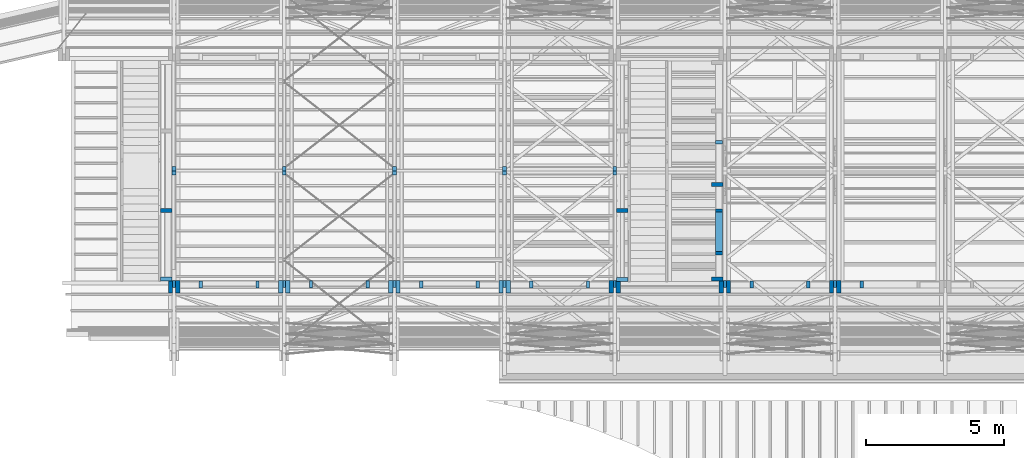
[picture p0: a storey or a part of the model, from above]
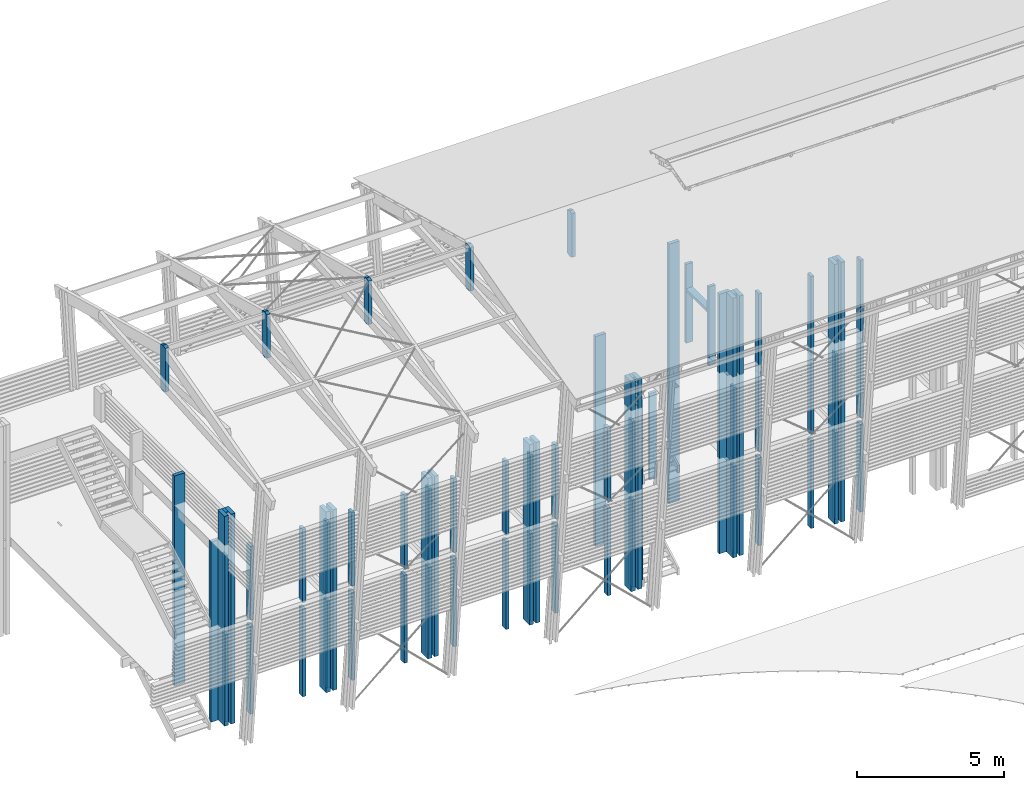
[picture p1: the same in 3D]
Properties of the parts of a building model (IFC2X3)

# File
Description: ViewDefinition [CoordinationView_V2.0]
File name: Export_V2
Time: 2021-08-31T17:11:27
Made in: cadwork

# IfcSite
RefElevation: 0 m

# IfcBuildingStorey, Storey 1
In: Building 1
Elevation: 0 m

# IfcBeam (1829)
In: Storey 1
Name | Material | Width (m) | Height (m) | Length (m) | CrossSectionArea (m2) | OuterfaceArea (m2) | TotalSurfaceArea (m2) | GrossVolume (m3) | NetVolume (m3) | GrossWeight | NetWeight | Group | SubGroup | Utilisateur 1
187 x garde corp | Moabi | 0.04 | 0.2 | 3.8048 | 1.6 | 1.8263 | 1.8423 | 0.0304 | 0.0304 | 19.785 | 19.785 | garde corp | Garde-corps | S-BEAM-____-OTLN
369 x garde corp | Moabi | 0.04 | 0.2 | 3.806 | 1.6 | 1.8269 | 1.8429 | 0.0304 | 0.0304 | 19.7912 | 19.7912 | garde corp | Garde-corps | S-BEAM-____-OTLN
25 x Sommier Coursive | GL28h | 0.14 | 0.32 | 2.6285 | 14.336 | 2.3831 | 2.4727 | 0.1178 | 0.1121 | 0.5312 | 0.5058 | structure poteau / poutre | Structure secondaire
19 x Sous-glace | GL28h | 0.12 | 0.12 | 4.0038 | 1.728 | 1.921 | 1.9498 | 0.0577 | 0.0576 | 0.2601 | 0.26 | structure poteau / poutre | Façade OB
66 x garde corp | Moabi | 0.04 | 0.2 | 2 | 1.6 | 0.96 | 0.976 | 0.016 | 0.016 | 10.4 | 10.4 | garde corp | Garde-corps | S-BEAM-____-OTLN
74 x Solive | GL28h | 0.07 | 0.22 | 3.86 | 3.388 | 2.2388 | 2.2696 | 0.0594 | 0.0594 | 0.2682 | 0.2682 | plancher R+2 | Plancher Exterieur | S-BEAM-____-OTLN
14 x Solive | GL28h | 0.07 | 0.22 | 1.53 | 3.388 | 0.8874 | 0.9182 | 0.0236 | 0.0236 | 0.1063 | 0.1063 | plancher R+1 | Plancher Exterieur | S-BEAM-____-OTLN
13 x Solive | GL28h | 0.07 | 0.22 | 1.58 | 3.388 | 0.9164 | 0.9472 | 0.0243 | 0.0243 | 0.1098 | 0.1098 | plancher R+2 | Plancher Exterieur | S-BEAM-____-OTLN
69 x Solive | GL28h | 0.07 | 0.22 | 3.86 | 3.388 | 2.2388 | 2.2696 | 0.0594 | 0.0594 | 0.2682 | 0.2682 | plancher R+1 | Plancher Exterieur | S-BEAM-____-OTLN
4 x Sommier | GL28h | 0.1 | 0.3 | 9.1632 | 9 | 7.3305 | 7.3905 | 0.2749 | 0.2749 | 1.2401 | 1.2401 | structure poteau / poutre | Structure primaire | S-BEAM-____-OTLN
188 x garde corp | Moabi | 0.04 | 0.2 | 3.8047 | 1.6 | 1.8263 | 1.8423 | 0.0304 | 0.0304 | 19.7845 | 19.7845 | garde corp | Garde-corps | S-BEAM-____-OTLN
28 x Sous-glace | GL28h | 0.12 | 0.12 | 8.0032 | 1.728 | 3.8415 | 3.8703 | 0.1152 | 0.1152 | 0.5199 | 0.5199 | structure poteau / poutre | Plancher intérieur
garde corp | Moabi | 0.04 | 0.2 | 2.8818 | 1.6 | 1.3384 | 1.3544 | 0.0231 | 0.0223 | 14.9852 | 14.4634 | garde corp | Garde-corps | S-BEAM-____-OTLN
24 x Arbalétrier | GL28h | 0.14 | 0.46 | 7.5286 | 29.624 | 8.9626 | 9.0914 | 0.4848 | 0.4809 | 2.1871 | 2.1692 | charpente | Surtoiture | S-BEAM-____-OTLN
6 x Arbalétrier | GL28h | 0.07 | 0.22 | 1.2244 | 3.388 | 0.6936 | 0.7244 | 0.0189 | 0.0184 | 0.0851 | 0.083 | charpente | Surtoiture | S-BEAM-____-OTLN
36 x garde corp | Moabi | 0.04 | 0.2 | 0.9516 | 1.6 | 0.4568 | 0.4728 | 0.0076 | 0.0076 | 4.9482 | 4.9482 | garde corp | Garde-corps | S-BEAM-____-OTLN
2 x Solive | GL28h | 0.07 | 0.22 | 0.8113 | 3.388 | 0.4705 | 0.5013 | 0.0125 | 0.0125 | 0.0564 | 0.0564 | plancher R+1 | Plancher Exterieur | S-BEAM-____-OTLN
2 x pannes | GL28h | 0.07 | 0.22 | 34.1022 | 3.388 | 19.7782 | 19.809 | 0.5252 | 0.5251 | 2.3691 | 2.369 | charpente | Empannage | S-BEAM-____-OTLN
Buton | GL28h | 0.26 | 0.32 | 7.7232 | 26.624 | 8.9589 | 9.1253 | 0.6426 | 0.6426 | 2.8987 | 2.8987 | structure poteau / poutre | Structure primaire | S-BEAM-____-OTLN
40 x Sommier | GL28h | 0.16 | 0.46 | 7.9632 | 33.856 | 9.8743 | 10.0215 | 0.5861 | 0.5861 | 2.6439 | 2.6439 | structure poteau / poutre | Structure primaire | S-BEAM-____-OTLN
8 x carrelet | GL28h | 0.07 | 0.07 | 3.5 | 0.343 | 0.98 | 0.9898 | 0.0172 | 0.0172 | 0.0774 | 0.0774 | plancher extérieur | Platelage
14 x Solive | GL28h | 0.07 | 0.22 | 1.58 | 3.388 | 0.9164 | 0.9472 | 0.0243 | 0.0243 | 0.1098 | 0.1098 | plancher R+1 | Plancher Exterieur | S-BEAM-____-OTLN
16 x garde corp | Moabi | 0.04 | 0.2 | 4.2356 | 1.6 | 2.0331 | 2.0491 | 0.0339 | 0.0339 | 22.0249 | 22.0249 | garde corp | Garde-corps | S-BEAM-____-OTLN
2 x garde corp | Moabi | 0.04 | 0.2 | 1.3533 | 1.6 | 0.6042 | 0.6202 | 0.0108 | 0.01 | 7.0372 | 6.5092 | garde corp | Garde-corps | S-BEAM-____-OTLN
15 x Solive | GL28h | 0.07 | 0.22 | 0.4614 | 3.388 | 0.2676 | 0.2984 | 0.0071 | 0.0071 | 0.0321 | 0.0321 | plancher R+1 | Plancher Exterieur | S-BEAM-____-OTLN
garde corp | Moabi | 0.04 | 0.2 | 2.6655 | 1.6 | 1.234 | 1.25 | 0.0213 | 0.0205 | 13.8608 | 13.3328 | garde corp | Garde-corps | S-BEAM-____-OTLN
2 x Sous-glace | GL28h | 0.12 | 0.12 | 3.5091 | 1.728 | 1.6844 | 1.7132 | 0.0505 | 0.0505 | 0.2279 | 0.2279 | structure poteau / poutre | Plancher intérieur
4 x Buton | GL28h | 0.26 | 0.52 | 2.3516 | 70.304 | 3.6685 | 3.9389 | 0.3179 | 0.3179 | 1.4342 | 1.4342 | structure poteau / poutre | Structure primaire | S-BEAM-____-OTLN
41 x Buton | GL28h | 0.26 | 0.26 | 3.58 | 17.576 | 3.7232 | 3.8584 | 0.242 | 0.242 | 1.0917 | 1.0917 | structure poteau / poutre | Structure primaire | S-BEAM-____-OTLN
14 x garde corp | Moabi | 0.04 | 0.2 | 3.819 | 1.6 | 1.8331 | 1.8491 | 0.0306 | 0.0306 | 19.8588 | 19.8588 | garde corp | Garde-corps | S-BEAM-____-OTLN
30 x Sommier | GL28h | 0.1 | 0.1 | 7.9632 | 1 | 3.1853 | 3.2053 | 0.0796 | 0.0796 | 0.3592 | 0.3592 | structure poteau / poutre | Structure primaire | S-BEAM-____-OTLN
15 x Buton | GL28h | 0.09 | 0.22 | 3.86 | 4.356 | 2.3932 | 2.4328 | 0.0764 | 0.0764 | 0.3448 | 0.3448 | charpente | Surtoiture
15 x Poutre - Bois de construction | GL28h | 0.07 | 0.07 | 16.14 | 0.343 | 4.5192 | 4.529 | 0.0791 | 0.0791 | 0.3568 | 0.3568 | plancher R+2
2 x pannes | GL28h | 0.07 | 0.22 | 34.056 | 3.388 | 19.7515 | 19.7823 | 0.5245 | 0.5244 | 2.3659 | 2.3658 | charpente | Empannage | S-BEAM-____-OTLN
2 x pannes | GL28h | 0.07 | 0.22 | 34.1252 | 3.388 | 19.7916 | 19.8224 | 0.5255 | 0.5255 | 2.3707 | 2.3706 | charpente | Empannage | S-BEAM-____-OTLN
2 x garde corp | Moabi | 0.04 | 0.2 | 1.4537 | 1.6 | 0.6523 | 0.6683 | 0.0116 | 0.0108 | 7.559 | 7.031 | garde corp | Garde-corps | S-BEAM-____-OTLN
2 x pannes | GL28h | 0.07 | 0.22 | 34.0791 | 3.388 | 19.7648 | 19.7956 | 0.5248 | 0.5248 | 2.3675 | 2.3674 | charpente | Empannage | S-BEAM-____-OTLN
2 x pannes | GL28h | 0.07 | 0.22 | 34.1483 | 3.388 | 19.805 | 19.8358 | 0.5259 | 0.5259 | 2.3723 | 2.3722 | charpente | Empannage | S-BEAM-____-OTLN
32 x garde corp | Moabi | 0.04 | 0.2 | 6.9116 | 1.6 | 3.3176 | 3.3336 | 0.0553 | 0.0553 | 35.9402 | 35.9402 | garde corp | Garde-corps | S-BEAM-____-OTLN
garde corp | Moabi | 0.04 | 0.2 | 2.5473 | 1.6 | 1.1778 | 1.1938 | 0.0204 | 0.0196 | 13.246 | 12.7241 | garde corp | Garde-corps | S-BEAM-____-OTLN
6 x carrelet | GL28h | 0.05 | 0.08 | 20.42 | 0.32 | 5.3092 | 5.3172 | 0.0817 | 0.0817 | 0.3685 | 0.3685 | charpente | Empannage | S-BEAM-____-OTLN
2 x garde corp | Moabi | 0.04 | 0.2 | 3.0669 | 1.6 | 1.4267 | 1.4427 | 0.0245 | 0.0237 | 15.9481 | 15.4201 | garde corp | Garde-corps | S-BEAM-____-OTLN
pannes | GL28h | 0.09 | 0.22 | 34.1813 | 4.356 | 21.1911 | 21.2307 | 0.6768 | 0.6767 | 3.053 | 3.0529 | charpente | Empannage
2 x pannes | GL28h | 0.07 | 0.22 | 34.0329 | 3.388 | 19.7381 | 19.7689 | 0.5241 | 0.5241 | 2.3643 | 2.3642 | charpente | Empannage | S-BEAM-____-OTLN
14 x Poutre - Bois de construction | GL28h | 0.07 | 0.07 | 4.02 | 0.343 | 1.1256 | 1.1354 | 0.0197 | 0.0197 | 0.0889 | 0.0889 | plancher R+2
2 x pannes | GL28h | 0.07 | 0.22 | 33.9637 | 3.388 | 19.6979 | 19.7287 | 0.523 | 0.523 | 2.3595 | 2.3593 | charpente | Empannage | S-BEAM-____-OTLN
pannes | GL28h | 0.09 | 0.22 | 34.1717 | 4.356 | 21.1852 | 21.2248 | 0.6766 | 0.6766 | 3.0522 | 3.052 | charpente | Empannage
2 x garde corp | Moabi | 0.04 | 0.2 | 1.1693 | 1.6 | 0.5159 | 0.5319 | 0.0094 | 0.0085 | 6.0806 | 5.5526 | garde corp | Garde-corps | S-BEAM-____-OTLN
2 x pannes | GL28h | 0.09 | 0.22 | 33.9871 | 4.356 | 21.0707 | 21.1103 | 0.6729 | 0.6729 | 3.0357 | 3.0355 | charpente | Empannage
2 x garde corp | Moabi | 0.04 | 0.2 | 1.0188 | 1.6 | 0.4436 | 0.4596 | 0.0082 | 0.0073 | 5.2979 | 4.7699 | garde corp | Garde-corps | S-BEAM-____-OTLN
2 x pannes | GL28h | 0.07 | 0.22 | 34.0099 | 3.388 | 19.7247 | 19.7555 | 0.5238 | 0.5237 | 2.3627 | 2.3626 | charpente | Empannage | S-BEAM-____-OTLN
12 x potelet | GL28h | 0.07 | 0.168 | 0.38 | 1.9757 | 0.1809 | 0.2044 | 0.0045 | 0.0045 | 0.0202 | 0.0202 | charpente | Surtoiture
2 x garde corp | Moabi | 0.04 | 0.2 | 2.9833 | 1.6 | 1.3866 | 1.4026 | 0.0239 | 0.0231 | 15.5132 | 14.9852 | garde corp | Garde-corps | S-BEAM-____-OTLN
6 x Rive | GL28h | 0.07 | 0.22 | 3.58 | 3.388 | 2.0764 | 2.1072 | 0.0551 | 0.0551 | 0.2487 | 0.2487 | façade | Structure primaire | S-BEAM-____-OTLN
14 x Sous-glace | GL28h | 0.1 | 0.1 | 4.0064 | 1 | 1.6014 | 1.6214 | 0.0401 | 0.04 | 0.1807 | 0.1806 | structure poteau / poutre | Plancher intérieur
2 x Buton | GL28h | 0.26 | 0.52 | 2.74 | 70.304 | 4.2744 | 4.5448 | 0.3704 | 0.3704 | 1.6711 | 1.6711 | structure poteau / poutre | Structure primaire | S-BEAM-____-OTLN
garde corp | Moabi | 0.04 | 0.2 | 2.5986 | 1.6 | 1.2019 | 1.2179 | 0.0208 | 0.02 | 13.513 | 12.985 | garde corp | Garde-corps | S-BEAM-____-OTLN
2 x garde corp | Moabi | 0.04 | 0.2 | 1.069 | 1.6 | 0.4677 | 0.4837 | 0.0086 | 0.0077 | 5.5588 | 5.0308 | garde corp | Garde-corps | S-BEAM-____-OTLN
2 x garde corp | Moabi | 0.04 | 0.2 | 2.9164 | 1.6 | 1.3545 | 1.3705 | 0.0233 | 0.0225 | 15.1654 | 14.6373 | garde corp | Garde-corps | S-BEAM-____-OTLN
Sous-glace | GL28h | 0.12 | 0.12 | 4.0038 | 1.728 | 1.921 | 1.9498 | 0.0577 | 0.0576 | 0.2601 | 0.26 | structure poteau / poutre | Plancher intérieur
24 x Entrait | GL28h | 0.14 | 0.32 | 10.6244 | 14.336 | 9.7694 | 9.859 | 0.476 | 0.4757 | 2.1471 | 2.146 | charpente | Surtoiture | S-BEAM-____-OTLN
4 x Buton | GL28h | 0.26 | 0.26 | 2.3516 | 17.576 | 2.4456 | 2.5808 | 0.159 | 0.159 | 0.7171 | 0.7171 | structure poteau / poutre | Structure primaire | S-BEAM-____-OTLN
garde corp | Moabi | 0.04 | 0.2 | 1.4871 | 1.6 | 0.6684 | 0.6844 | 0.0119 | 0.0111 | 7.7329 | 7.205 | garde corp | Garde-corps | S-BEAM-____-OTLN
garde corp | Moabi | 0.04 | 0.14 | 10.7403 | 0.784 | 3.8665 | 3.8777 | 0.0601 | 0.0601 | 39.0948 | 39.0948 | garde corp | Garde-corps | S-BEAM-____-OTLN
2 x garde corp | Moabi | 0.04 | 0.2 | 1.4035 | 1.6 | 0.6282 | 0.6442 | 0.0112 | 0.0104 | 7.2981 | 6.7701 | garde corp | Garde-corps | S-BEAM-____-OTLN
2 x garde corp | Moabi | 0.04 | 0.2 | 1.5038 | 1.6 | 0.6764 | 0.6924 | 0.012 | 0.0112 | 7.8199 | 7.2919 | garde corp | Garde-corps | S-BEAM-____-OTLN
2 x garde corp | Moabi | 0.04 | 0.2 | 1.3868 | 1.6 | 0.6202 | 0.6362 | 0.0111 | 0.0103 | 7.2112 | 6.6831 | garde corp | Garde-corps | S-BEAM-____-OTLN
2 x Buton | GL28h | 0.26 | 0.26 | 2.74 | 17.576 | 2.8496 | 2.9848 | 0.1852 | 0.1852 | 0.8356 | 0.8356 | structure poteau / poutre | Structure primaire | S-BEAM-____-OTLN
Solive | GL28h | 0.07 | 0.22 | 3.413 | 3.388 | 1.9717 | 2.0025 | 0.0526 | 0.0523 | 0.2371 | 0.236 | plancher R+1 | Plancher Exterieur | S-BEAM-____-OTLN
2 x garde corp | Moabi | 0.04 | 0.2 | 1.3366 | 1.6 | 0.5961 | 0.6121 | 0.0107 | 0.0099 | 6.9503 | 6.4222 | garde corp | Garde-corps | S-BEAM-____-OTLN
25 x Sommier Coursive | GL28h | 0.14 | 0.32 | 2.29 | 14.336 | 2.0716 | 2.1612 | 0.1026 | 0.097 | 0.4628 | 0.4374 | structure poteau / poutre | Structure secondaire
11 x garde corp | Moabi | 0.04 | 0.2 | 3.805 | 1.6 | 1.8264 | 1.8424 | 0.0304 | 0.0304 | 19.786 | 19.786 | garde corp | Garde-corps | S-BEAM-____-OTLN
9 x Solive | GL28h | 0.07 | 0.22 | 3.8601 | 3.388 | 2.2389 | 2.2697 | 0.0594 | 0.0594 | 0.2682 | 0.2682 | plancher R+2 | Plancher Exterieur | S-BEAM-____-OTLN
7 x garde corp | Moabi | 0.04 | 0.2 | 3.0093 | 1.6 | 1.4445 | 1.4605 | 0.0241 | 0.0241 | 15.6485 | 15.6485 | garde corp | Garde-corps | S-BEAM-____-OTLN
2 x garde corp | Moabi | 0.04 | 0.2 | 0.6843 | 1.6 | 0.2831 | 0.2991 | 0.0055 | 0.0047 | 3.5585 | 3.0305 | garde corp | Garde-corps | S-BEAM-____-OTLN
carrelet | GL28h | 0.07 | 0.07 | 2.8692 | 0.343 | 0.8034 | 0.8132 | 0.0141 | 0.0141 | 0.0634 | 0.0634 | plancher extérieur | Platelage
Buton | GL28h | 0.26 | 0.52 | 7.7232 | 70.304 | 12.0481 | 12.3185 | 1.0442 | 1.0442 | 4.7103 | 4.7103 | structure poteau / poutre | Structure primaire | S-BEAM-____-OTLN
2 x garde corp | Moabi | 0.04 | 0.2 | 2.9551 | 1.6 | 1.4185 | 1.4345 | 0.0236 | 0.0236 | 15.3667 | 15.3667 | garde corp | Garde-corps | S-BEAM-____-OTLN
2 x garde corp | Moabi | 0.04 | 0.2 | 1.37 | 1.6 | 0.6122 | 0.6282 | 0.011 | 0.0101 | 7.1242 | 6.5962 | garde corp | Garde-corps | S-BEAM-____-OTLN
garde corp | Moabi | 0.04 | 0.14 | 10.7591 | 0.784 | 3.8733 | 3.8845 | 0.0603 | 0.0603 | 39.1631 | 39.1631 | garde corp | Garde-corps | S-BEAM-____-OTLN
2 x Sommier | GL28h | 0.14 | 0.36 | 3.73 | 18.144 | 3.73 | 3.8308 | 0.188 | 0.188 | 0.848 | 0.848 | structure poteau / poutre | Structure primaire | S-BEAM-____-OTLN
garde corp | Moabi | 0.04 | 0.2 | 1.4369 | 1.6 | 0.6443 | 0.6603 | 0.0115 | 0.0107 | 7.472 | 6.9441 | garde corp | Garde-corps | S-BEAM-____-OTLN
carrelet | GL28h | 0.07 | 0.07 | 2.5066 | 0.343 | 0.7018 | 0.7116 | 0.0123 | 0.0123 | 0.0554 | 0.0554 | plancher extérieur | Platelage
2 x garde corp | Moabi | 0.04 | 0.2 | 1.4704 | 1.6 | 0.6604 | 0.6764 | 0.0118 | 0.011 | 7.646 | 7.118 | garde corp | Garde-corps | S-BEAM-____-OTLN
garde corp | Moabi | 0.04 | 0.2 | 2.8976 | 1.6 | 1.3464 | 1.3624 | 0.0232 | 0.0224 | 15.0678 | 14.5504 | garde corp | Garde-corps | S-BEAM-____-OTLN
15 x carrelet | GL28h | 0.07 | 0.07 | 4.458 | 0.343 | 1.2482 | 1.258 | 0.0218 | 0.0218 | 0.0985 | 0.0985 | plancher extérieur | Platelage
2 x garde corp | Moabi | 0.04 | 0.2 | 2.6154 | 1.6 | 1.21 | 1.226 | 0.0209 | 0.0201 | 13.5999 | 13.0719 | garde corp | Garde-corps | S-BEAM-____-OTLN
garde corp | Moabi | 0.04 | 0.2 | 3.0335 | 1.6 | 1.4106 | 1.4266 | 0.0243 | 0.0235 | 15.7741 | 15.2461 | garde corp | Garde-corps | S-BEAM-____-OTLN
2 x garde corp | Moabi | 0.04 | 0.2 | 0.9854 | 1.6 | 0.4276 | 0.4436 | 0.0079 | 0.0071 | 5.1239 | 4.5959 | garde corp | Garde-corps | S-BEAM-____-OTLN
garde corp | Moabi | 0.04 | 0.2 | 2.9947 | 1.6 | 1.3944 | 1.4104 | 0.024 | 0.0232 | 15.5724 | 15.072 | garde corp | Garde-corps | S-BEAM-____-OTLN
7 x garde corp | Moabi | 0.04 | 0.14 | 8.8432 | 0.784 | 3.1835 | 3.1947 | 0.0495 | 0.0495 | 32.1891 | 32.1891 | garde corp | Garde-corps | S-BEAM-____-OTLN
2 x Sous-glace | GL28h | 0.12 | 0.12 | 3.62 | 1.728 | 1.7376 | 1.7664 | 0.0521 | 0.0521 | 0.2352 | 0.2352 | structure poteau / poutre | Plancher intérieur | S-BEAM-____-OTLN
2 x Sous-glace | GL28h | 0.14 | 0.12 | 1.9 | 2.016 | 0.988 | 1.0216 | 0.0319 | 0.0319 | 0.144 | 0.144 | structure poteau / poutre | Plancher intérieur | S-BEAM-____-OTLN
carrelet | GL28h | 0.07 | 0.07 | 1.6083 | 0.343 | 0.4503 | 0.4601 | 0.0079 | 0.0079 | 0.0355 | 0.0355 | plancher extérieur | Platelage
carrelet | GL28h | 0.07 | 0.07 | 1.1228 | 0.343 | 0.3144 | 0.3242 | 0.0055 | 0.0055 | 0.0248 | 0.0248 | plancher extérieur | Platelage
carrelet | GL28h | 0.07 | 0.07 | 0.1148 | 0.343 | 0.0321 | 0.0419 | 0.0006 | 0.0006 | 0.0025 | 0.0025 | plancher extérieur | Platelage
10 x Buton | GL28h | 0.26 | 0.32 | 3.58 | 26.624 | 4.1528 | 4.3192 | 0.2979 | 0.2979 | 1.3436 | 1.3436 | structure poteau / poutre | Structure primaire | S-BEAM-____-OTLN
Poutre - Bois de construction | GL28h | 0.07 | 0.07 | 3.88 | 0.343 | 1.0864 | 1.0962 | 0.019 | 0.019 | 0.0858 | 0.0858 | plancher R+2
garde corp | Moabi | 0.04 | 0.2 | 2.5308 | 1.6 | 1.1698 | 1.1858 | 0.0202 | 0.0194 | 13.1601 | 12.6371 | garde corp | Garde-corps | S-BEAM-____-OTLN
carrelet | GL28h | 0.07 | 0.07 | 0.109 | 0.343 | 0.0305 | 0.0403 | 0.0005 | 0.0005 | 0.0024 | 0.0024 | plancher extérieur | Platelage
4 x Sommier | GL28h | 0.14 | 0.36 | 8.0032 | 18.144 | 8.0032 | 8.104 | 0.4034 | 0.4034 | 1.8196 | 1.8196 | structure poteau / poutre | Structure primaire | S-BEAM-____-OTLN
carrelet | GL28h | 0.07 | 0.07 | 0.2271 | 0.343 | 0.0636 | 0.0734 | 0.0011 | 0.0011 | 0.005 | 0.005 | plancher extérieur | Platelage
carrelet | GL28h | 0.07 | 0.07 | 0.7099 | 0.343 | 0.1988 | 0.2086 | 0.0035 | 0.0035 | 0.0157 | 0.0157 | plancher extérieur | Platelage
carrelet | GL28h | 0.07 | 0.07 | 1.8872 | 0.343 | 0.5284 | 0.5382 | 0.0092 | 0.0092 | 0.0417 | 0.0417 | plancher extérieur | Platelage
carrelet | GL28h | 0.07 | 0.07 | 0.9052 | 0.343 | 0.2535 | 0.2633 | 0.0044 | 0.0044 | 0.02 | 0.02 | plancher extérieur | Platelage
carrelet | GL28h | 0.07 | 0.07 | 4.0521 | 0.343 | 1.1346 | 1.1444 | 0.0199 | 0.0199 | 0.0896 | 0.0896 | plancher extérieur | Platelage
carrelet | GL28h | 0.07 | 0.07 | 3.2431 | 0.343 | 0.9081 | 0.9179 | 0.0159 | 0.0159 | 0.0717 | 0.0717 | plancher extérieur | Platelage
carrelet | GL28h | 0.07 | 0.07 | 0.5202 | 0.343 | 0.1457 | 0.1555 | 0.0025 | 0.0025 | 0.0115 | 0.0115 | plancher extérieur | Platelage
carrelet | GL28h | 0.07 | 0.07 | 1.7011 | 0.343 | 0.4763 | 0.4861 | 0.0083 | 0.0083 | 0.0376 | 0.0376 | plancher extérieur | Platelage
15 x Solive | GL28h | 0.07 | 0.22 | 0.8039 | 3.388 | 0.4663 | 0.4971 | 0.0124 | 0.0124 | 0.0558 | 0.0558 | plancher R+2 | Plancher Exterieur | S-BEAM-____-OTLN
carrelet | GL28h | 0.07 | 0.07 | 3.6225 | 0.343 | 1.0143 | 1.0241 | 0.0178 | 0.0178 | 0.0801 | 0.0801 | plancher extérieur | Platelage
carrelet | GL28h | 0.07 | 0.07 | 1.1271 | 0.343 | 0.3156 | 0.3254 | 0.0055 | 0.0055 | 0.0249 | 0.0249 | plancher extérieur | Platelage
garde corp | Moabi | 0.04 | 0.2 | 2.2473 | 1.6 | 1.0333 | 1.0493 | 0.018 | 0.0172 | 11.686 | 11.1586 | garde corp | Garde-corps | S-BEAM-____-OTLN
2 x carrelet | GL28h | 0.07 | 0.07 | 3.5 | 0.343 | 0.98 | 0.9898 | 0.0171 | 0.0171 | 0.0774 | 0.0774 | plancher extérieur | Platelage
2 x garde corp | Moabi | 0.04 | 0.2 | 2.515 | 1.6 | 1.1618 | 1.1778 | 0.0201 | 0.0193 | 13.0781 | 12.5501 | garde corp | Garde-corps | S-BEAM-____-OTLN
carrelet | GL28h | 0.07 | 0.07 | 2.1885 | 0.343 | 0.6128 | 0.6226 | 0.0107 | 0.0107 | 0.0484 | 0.0484 | plancher extérieur | Platelage
garde corp | Moabi | 0.04 | 0.2 | 2.5485 | 1.6 | 1.1778 | 1.1938 | 0.0204 | 0.0196 | 13.2521 | 12.7241 | garde corp | Garde-corps | S-BEAM-____-OTLN
garde corp | Moabi | 0.04 | 0.2 | 2.198 | 1.6 | 1.0163 | 1.0323 | 0.0176 | 0.0169 | 11.4295 | 10.9821 | garde corp | Garde-corps | S-BEAM-____-OTLN
garde corp | Moabi | 0.04 | 0.2 | 2.2307 | 1.6 | 1.0253 | 1.0413 | 0.0178 | 0.017 | 11.5996 | 11.0717 | garde corp | Garde-corps | S-BEAM-____-OTLN
carrelet | GL28h | 0.07 | 0.07 | 2.9888 | 0.343 | 0.8369 | 0.8467 | 0.0146 | 0.0146 | 0.0661 | 0.0661 | plancher extérieur | Platelage
garde corp | Moabi | 0.04 | 0.2 | 2.481 | 1.6 | 1.1457 | 1.1617 | 0.0198 | 0.019 | 12.901 | 12.3762 | garde corp | Garde-corps | S-BEAM-____-OTLN
Buton | GL28h | 0.26 | 0.32 | 7.8632 | 26.624 | 9.1213 | 9.2877 | 0.6542 | 0.6542 | 2.9512 | 2.9512 | structure poteau / poutre | Structure primaire | S-BEAM-____-OTLN
garde corp | Moabi | 0.04 | 0.14 | 8.8431 | 0.784 | 3.1835 | 3.1947 | 0.0495 | 0.0495 | 32.1889 | 32.1889 | garde corp | Garde-corps | S-BEAM-____-OTLN
carrelet | GL28h | 0.07 | 0.07 | 0.3599 | 0.343 | 0.1008 | 0.1106 | 0.0018 | 0.0018 | 0.008 | 0.008 | plancher extérieur | Platelage
5 x garde corp | Moabi | 0.04 | 0.14 | 10.8516 | 0.784 | 3.9066 | 3.9178 | 0.0608 | 0.0608 | 39.4997 | 39.4997 | garde corp | Garde-corps | S-BEAM-____-OTLN
garde corp | Moabi | 0.04 | 0.2 | 2.5652 | 1.6 | 1.1859 | 1.2019 | 0.0205 | 0.0197 | 13.339 | 12.811 | garde corp | Garde-corps | S-BEAM-____-OTLN
garde corp | Moabi | 0.04 | 0.2 | 2.197 | 1.6 | 1.0093 | 1.0253 | 0.0176 | 0.0168 | 11.4243 | 10.8977 | garde corp | Garde-corps | S-BEAM-____-OTLN
garde corp | Moabi | 0.04 | 0.2 | 2.214 | 1.6 | 1.0173 | 1.0333 | 0.0177 | 0.0169 | 11.5127 | 10.9847 | garde corp | Garde-corps | S-BEAM-____-OTLN
2 x garde corp | Moabi | 0.04 | 0.2 | 1.1359 | 1.6 | 0.4998 | 0.5158 | 0.0091 | 0.0083 | 5.9067 | 5.3786 | garde corp | Garde-corps | S-BEAM-____-OTLN
garde corp | Moabi | 0.04 | 0.2 | 2.2809 | 1.6 | 1.0494 | 1.0654 | 0.0182 | 0.0174 | 11.8606 | 11.3326 | garde corp | Garde-corps | S-BEAM-____-OTLN
garde corp | Moabi | 0.04 | 0.2 | 2.4975 | 1.6 | 1.1538 | 1.1698 | 0.02 | 0.0192 | 12.9868 | 12.4631 | garde corp | Garde-corps | S-BEAM-____-OTLN
2 x garde corp | Moabi | 0.04 | 0.2 | 2.5819 | 1.6 | 1.1939 | 1.2099 | 0.0207 | 0.0198 | 13.426 | 12.898 | garde corp | Garde-corps | S-BEAM-____-OTLN
garde corp | Moabi | 0.04 | 0.2 | 2.6304 | 1.6 | 1.218 | 1.234 | 0.021 | 0.0202 | 13.6779 | 13.1589 | garde corp | Garde-corps | S-BEAM-____-OTLN
garde corp | Moabi | 0.04 | 0.2 | 2.5981 | 1.6 | 1.2019 | 1.2179 | 0.0208 | 0.02 | 13.51 | 12.985 | garde corp | Garde-corps | S-BEAM-____-OTLN
garde corp | Moabi | 0.04 | 0.2 | 2.2639 | 1.6 | 1.0414 | 1.0574 | 0.0181 | 0.0173 | 11.7723 | 11.2456 | garde corp | Garde-corps | S-BEAM-____-OTLN
carrelet | GL28h | 0.07 | 0.07 | 0.5934 | 0.343 | 0.1662 | 0.176 | 0.0029 | 0.0029 | 0.0131 | 0.0131 | plancher extérieur | Platelage
carrelet | GL28h | 0.07 | 0.07 | 2.3285 | 0.343 | 0.652 | 0.6618 | 0.0114 | 0.0114 | 0.0515 | 0.0515 | plancher extérieur | Platelage
carrelet | GL28h | 0.07 | 0.07 | 1.3628 | 0.343 | 0.3816 | 0.3914 | 0.0067 | 0.0067 | 0.0301 | 0.0301 | plancher extérieur | Platelage
garde corp | Moabi | 0.04 | 0.2 | 3.1048 | 1.6 | 1.4449 | 1.4609 | 0.0248 | 0.024 | 16.1449 | 15.6169 | garde corp | Garde-corps | S-BEAM-____-OTLN
2 x garde corp | Moabi | 0.04 | 0.2 | 3.0168 | 1.6 | 1.4026 | 1.4186 | 0.0241 | 0.0233 | 15.6872 | 15.1591 | garde corp | Garde-corps | S-BEAM-____-OTLN
garde corp | Moabi | 0.04 | 0.2 | 2.9499 | 1.6 | 1.3705 | 1.3865 | 0.0236 | 0.0228 | 15.3393 | 14.8113 | garde corp | Garde-corps | S-BEAM-____-OTLN
garde corp | Moabi | 0.04 | 0.2 | 2.8997 | 1.6 | 1.3464 | 1.3624 | 0.0232 | 0.0224 | 15.0784 | 14.5504 | garde corp | Garde-corps | S-BEAM-____-OTLN
2 x garde corp | Moabi | 0.04 | 0.2 | 1.1861 | 1.6 | 0.5239 | 0.5399 | 0.0095 | 0.0087 | 6.1676 | 5.6395 | garde corp | Garde-corps | S-BEAM-____-OTLN
2 x garde corp | Moabi | 0.04 | 0.2 | 1.0523 | 1.6 | 0.4597 | 0.4757 | 0.0084 | 0.0076 | 5.4718 | 4.9438 | garde corp | Garde-corps | S-BEAM-____-OTLN
2 x garde corp | Moabi | 0.04 | 0.2 | 3.0502 | 1.6 | 1.4187 | 1.4347 | 0.0244 | 0.0236 | 15.8611 | 15.3331 | garde corp | Garde-corps | S-BEAM-____-OTLN
2 x garde corp | Moabi | 0.04 | 0.2 | 3.0881 | 1.6 | 1.4368 | 1.4528 | 0.0247 | 0.0239 | 16.0579 | 15.5299 | garde corp | Garde-corps | S-BEAM-____-OTLN
2 x garde corp | Moabi | 0.04 | 0.2 | 2.9666 | 1.6 | 1.3785 | 1.3945 | 0.0237 | 0.0229 | 15.4263 | 14.8982 | garde corp | Garde-corps | S-BEAM-____-OTLN
2 x garde corp | Moabi | 0.04 | 0.2 | 3.0837 | 1.6 | 1.4347 | 1.4507 | 0.0247 | 0.0239 | 16.035 | 15.507 | garde corp | Garde-corps | S-BEAM-____-OTLN
garde corp | Moabi | 0.04 | 0.2 | 0.8769 | 1.6 | 0.4209 | 0.4369 | 0.007 | 0.007 | 4.56 | 4.56 | garde corp | Garde-corps | S-BEAM-____-OTLN
garde corp | Moabi | 0.04 | 0.2 | 0.9519 | 1.6 | 0.4115 | 0.4275 | 0.0076 | 0.0068 | 4.95 | 4.422 | garde corp | Garde-corps | S-BEAM-____-OTLN
2 x garde corp | Moabi | 0.04 | 0.2 | 1.0021 | 1.6 | 0.4356 | 0.4516 | 0.008 | 0.0072 | 5.2109 | 4.6829 | garde corp | Garde-corps | S-BEAM-____-OTLN
garde corp | Moabi | 0.04 | 0.2 | 0.8534 | 1.6 | 0.4096 | 0.4256 | 0.0068 | 0.0068 | 4.4376 | 4.4376 | garde corp | Garde-corps | S-BEAM-____-OTLN
garde corp | Moabi | 0.04 | 0.2 | 0.9686 | 1.6 | 0.4195 | 0.4355 | 0.0077 | 0.0069 | 5.037 | 4.509 | garde corp | Garde-corps | S-BEAM-____-OTLN
2 x garde corp | Moabi | 0.04 | 0.2 | 1.1526 | 1.6 | 0.5078 | 0.5238 | 0.0092 | 0.0084 | 5.9936 | 5.4656 | garde corp | Garde-corps | S-BEAM-____-OTLN
garde corp | Moabi | 0.04 | 0.2 | 3.1215 | 1.6 | 1.4529 | 1.4689 | 0.025 | 0.0242 | 16.2319 | 15.7038 | garde corp | Garde-corps | S-BEAM-____-OTLN
2 x garde corp | Moabi | 0.04 | 0.2 | 1.4202 | 1.6 | 0.6363 | 0.6523 | 0.0114 | 0.0105 | 7.3851 | 6.8571 | garde corp | Garde-corps | S-BEAM-____-OTLN
2 x garde corp | Moabi | 0.04 | 0.2 | 1.1024 | 1.6 | 0.4837 | 0.4997 | 0.0088 | 0.008 | 5.7327 | 5.2047 | garde corp | Garde-corps | S-BEAM-____-OTLN
2 x garde corp | Moabi | 0.04 | 0.2 | 0.7345 | 1.6 | 0.3071 | 0.3231 | 0.0059 | 0.0051 | 3.8194 | 3.2914 | garde corp | Garde-corps | S-BEAM-____-OTLN
2 x garde corp | Moabi | 0.04 | 0.2 | 1.0355 | 1.6 | 0.4516 | 0.4676 | 0.0083 | 0.0075 | 5.3848 | 4.8568 | garde corp | Garde-corps | S-BEAM-____-OTLN
garde corp | Moabi | 0.04 | 0.2 | 1.4369 | 1.6 | 0.6443 | 0.6603 | 0.0115 | 0.0107 | 7.4721 | 6.9441 | garde corp | Garde-corps | S-BEAM-____-OTLN
2 x garde corp | Moabi | 0.04 | 0.2 | 1.5206 | 1.6 | 0.6844 | 0.7004 | 0.0122 | 0.0114 | 7.9069 | 7.3789 | garde corp | Garde-corps | S-BEAM-____-OTLN
2 x garde corp | Moabi | 0.04 | 0.2 | 0.6676 | 1.6 | 0.275 | 0.291 | 0.0053 | 0.0045 | 3.4716 | 2.9435 | garde corp | Garde-corps | S-BEAM-____-OTLN
2 x garde corp | Moabi | 0.04 | 0.2 | 0.7011 | 1.6 | 0.2911 | 0.3071 | 0.0056 | 0.0048 | 3.6455 | 3.1175 | garde corp | Garde-corps | S-BEAM-____-OTLN
2 x garde corp | Moabi | 0.04 | 0.2 | 1.2028 | 1.6 | 0.5319 | 0.5479 | 0.0096 | 0.0088 | 6.2545 | 5.7265 | garde corp | Garde-corps | S-BEAM-____-OTLN
garde corp | Moabi | 0.04 | 0.2 | 2.8662 | 1.6 | 1.3304 | 1.3464 | 0.0229 | 0.0221 | 14.9045 | 14.3764 | garde corp | Garde-corps | S-BEAM-____-OTLN
garde corp | Moabi | 0.04 | 0.2 | 1.4871 | 1.6 | 0.6684 | 0.6844 | 0.0119 | 0.0111 | 7.733 | 7.205 | garde corp | Garde-corps | S-BEAM-____-OTLN
garde corp | Moabi | 0.04 | 0.2 | 1.5373 | 1.6 | 0.6925 | 0.7085 | 0.0123 | 0.0115 | 7.9938 | 7.4659 | garde corp | Garde-corps | S-BEAM-____-OTLN
garde corp | Moabi | 0.04 | 0.2 | 2.883 | 1.6 | 1.3384 | 1.3544 | 0.0231 | 0.0223 | 14.9914 | 14.4634 | garde corp | Garde-corps | S-BEAM-____-OTLN
garde corp | Moabi | 0.04 | 0.2 | 2.6488 | 1.6 | 1.226 | 1.242 | 0.0212 | 0.0204 | 13.7739 | 13.2459 | garde corp | Garde-corps | S-BEAM-____-OTLN
2 x garde corp | Moabi | 0.04 | 0.2 | 3.1382 | 1.6 | 1.4609 | 1.4769 | 0.0251 | 0.0243 | 16.3188 | 15.7908 | garde corp | Garde-corps | S-BEAM-____-OTLN
garde corp | Moabi | 0.04 | 0.2 | 2.9331 | 1.6 | 1.3625 | 1.3785 | 0.0235 | 0.0227 | 15.2523 | 14.7243 | garde corp | Garde-corps | S-BEAM-____-OTLN
2 x garde corp | Moabi | 0.04 | 0.2 | 1.1192 | 1.6 | 0.4918 | 0.5078 | 0.009 | 0.0081 | 5.8197 | 5.2917 | garde corp | Garde-corps | S-BEAM-____-OTLN
2 x garde corp | Moabi | 0.04 | 0.2 | 1.0857 | 1.6 | 0.4757 | 0.4917 | 0.0087 | 0.0079 | 5.6458 | 5.1177 | garde corp | Garde-corps | S-BEAM-____-OTLN
garde corp | Moabi | 0.04 | 0.2 | 1.5373 | 1.6 | 0.6925 | 0.7085 | 0.0123 | 0.0115 | 7.9939 | 7.4659 | garde corp | Garde-corps | S-BEAM-____-OTLN
garde corp | Moabi | 0.04 | 0.2 | 2.9462 | 1.6 | 1.3704 | 1.3864 | 0.0236 | 0.0228 | 15.3202 | 14.8112 | garde corp | Garde-corps | S-BEAM-____-OTLN
Buton | GL28h | 0.26 | 0.32 | 2.5332 | 26.624 | 2.9385 | 3.1049 | 0.2108 | 0.2108 | 0.9507 | 0.9507 | structure poteau / poutre | Structure primaire | S-BEAM-____-OTLN
2 x garde corp | Moabi | 0.04 | 0.2 | 0.7512 | 1.6 | 0.3152 | 0.3312 | 0.006 | 0.0052 | 3.9064 | 3.3784 | garde corp | Garde-corps | S-BEAM-____-OTLN
2 x garde corp | Moabi | 0.04 | 0.2 | 1.554 | 1.6 | 0.7005 | 0.7165 | 0.0124 | 0.0116 | 8.0808 | 7.5528 | garde corp | Garde-corps | S-BEAM-____-OTLN
2 x garde corp | Moabi | 0.04 | 0.2 | 0.7178 | 1.6 | 0.2991 | 0.3151 | 0.0057 | 0.0049 | 3.7325 | 3.2044 | garde corp | Garde-corps | S-BEAM-____-OTLN
4 x Solive | GL28h | 0.07 | 0.22 | 3.8599 | 3.388 | 2.2387 | 2.2695 | 0.0594 | 0.0594 | 0.2681 | 0.2681 | plancher R+2 | Plancher Exterieur | S-BEAM-____-OTLN
garde corp | Moabi | 0.04 | 0.2 | 2.2297 | 1.6 | 1.0253 | 1.0413 | 0.0178 | 0.017 | 11.5945 | 11.0717 | garde corp | Garde-corps | S-BEAM-____-OTLN
garde corp | Moabi | 0.04 | 0.2 | 3.4393 | 1.6 | 1.6054 | 1.6214 | 0.0275 | 0.0267 | 17.8843 | 17.3562 | garde corp | Garde-corps | S-BEAM-____-OTLN
garde corp | Moabi | 0.04 | 0.2 | 2.6593 | 1.6 | 1.2338 | 1.2498 | 0.0213 | 0.0205 | 13.8285 | 13.3326 | garde corp | Garde-corps | S-BEAM-____-OTLN
garde corp | Moabi | 0.04 | 0.2 | 2.5202 | 1.6 | 1.1692 | 1.1852 | 0.0202 | 0.0194 | 13.1049 | 12.6359 | garde corp | Garde-corps | S-BEAM-____-OTLN
garde corp | Moabi | 0.04 | 0.2 | 2.647 | 1.6 | 1.226 | 1.242 | 0.0212 | 0.0204 | 13.7643 | 13.2459 | garde corp | Garde-corps | S-BEAM-____-OTLN
garde corp | Moabi | 0.04 | 0.2 | 3.3389 | 1.6 | 1.5573 | 1.5733 | 0.0267 | 0.0259 | 17.3624 | 16.8344 | garde corp | Garde-corps | S-BEAM-____-OTLN
garde corp | Moabi | 0.04 | 0.2 | 2.6321 | 1.6 | 1.218 | 1.234 | 0.0211 | 0.0202 | 13.6869 | 13.1589 | garde corp | Garde-corps | S-BEAM-____-OTLN
garde corp | Moabi | 0.04 | 0.2 | 2.9998 | 1.6 | 1.3946 | 1.4106 | 0.024 | 0.0232 | 15.5992 | 15.0722 | garde corp | Garde-corps | S-BEAM-____-OTLN
garde corp | Moabi | 0.04 | 0.2 | 2.2361 | 1.6 | 1.0327 | 1.0487 | 0.0179 | 0.0172 | 11.6275 | 11.1575 | garde corp | Garde-corps | S-BEAM-____-OTLN
garde corp | Moabi | 0.04 | 0.2 | 2.4783 | 1.6 | 1.1457 | 1.1617 | 0.0198 | 0.019 | 12.8872 | 12.3761 | garde corp | Garde-corps | S-BEAM-____-OTLN
garde corp | Moabi | 0.04 | 0.2 | 3.1212 | 1.6 | 1.4529 | 1.4689 | 0.025 | 0.0242 | 16.2304 | 15.7038 | garde corp | Garde-corps | S-BEAM-____-OTLN
garde corp | Moabi | 0.04 | 0.2 | 2.2741 | 1.6 | 1.0491 | 1.0651 | 0.0182 | 0.0174 | 11.8256 | 11.3323 | garde corp | Garde-corps | S-BEAM-____-OTLN
garde corp | Moabi | 0.04 | 0.2 | 2.1916 | 1.6 | 1.009 | 1.025 | 0.0175 | 0.0168 | 11.3965 | 10.8975 | garde corp | Garde-corps | S-BEAM-____-OTLN
garde corp | Moabi | 0.04 | 0.2 | 2.8642 | 1.6 | 1.3303 | 1.3463 | 0.0229 | 0.0221 | 14.8941 | 14.3764 | garde corp | Garde-corps | S-BEAM-____-OTLN
garde corp | Moabi | 0.04 | 0.2 | 2.5598 | 1.6 | 1.1857 | 1.2017 | 0.0205 | 0.0197 | 13.3108 | 12.8109 | garde corp | Garde-corps | S-BEAM-____-OTLN
garde corp | Moabi | 0.04 | 0.2 | 3.1001 | 1.6 | 1.4447 | 1.4607 | 0.0248 | 0.024 | 16.1205 | 15.6168 | garde corp | Garde-corps | S-BEAM-____-OTLN
garde corp | Moabi | 0.04 | 0.2 | 2.4907 | 1.6 | 1.1534 | 1.1694 | 0.0199 | 0.0192 | 12.9515 | 12.4627 | garde corp | Garde-corps | S-BEAM-____-OTLN
garde corp | Moabi | 0.04 | 0.2 | 2.2488 | 1.6 | 1.0404 | 1.0564 | 0.018 | 0.0173 | 11.6935 | 11.2433 | garde corp | Garde-corps | S-BEAM-____-OTLN
2 x Sous-glace | GL28h | 0.12 | 0.12 | 3.9941 | 1.728 | 1.9172 | 1.946 | 0.0575 | 0.0575 | 0.2595 | 0.2595 | structure poteau / poutre | Plancher intérieur
6 x garde corp | Moabi | 0.04 | 0.2 | 3.803 | 1.6 | 1.8254 | 1.8414 | 0.0304 | 0.0304 | 19.7756 | 19.7756 | garde corp | Garde-corps | S-BEAM-____-OTLN
Sommier | GL28h | 0.14 | 0.36 | 3.8477 | 18.144 | 3.8477 | 3.9485 | 0.1939 | 0.1939 | 0.8748 | 0.8748 | structure poteau / poutre | Structure primaire | S-BEAM-____-OTLN
2 x Solive | GL28h | 0.07 | 0.22 | 0.9438 | 3.388 | 0.5474 | 0.5782 | 0.0145 | 0.0145 | 0.0656 | 0.0656 | plancher R+2 | Plancher Exterieur | S-BEAM-____-OTLN
Solive | GL28h | 0.07 | 0.22 | 3.8481 | 3.388 | 2.2276 | 2.2584 | 0.0593 | 0.0591 | 0.2673 | 0.2668 | plancher R+1 | Plancher Exterieur | S-BEAM-____-OTLN
Buton | GL28h | 0.26 | 0.32 | 7.9632 | 26.624 | 9.2373 | 9.4037 | 0.6625 | 0.6625 | 2.9887 | 2.9887 | structure poteau / poutre | Structure primaire | S-BEAM-____-OTLN
3 x Solive | GL28h | 0.07 | 0.22 | 3.8598 | 3.388 | 2.2387 | 2.2695 | 0.0594 | 0.0594 | 0.2681 | 0.2681 | plancher R+2 | Plancher Exterieur | S-BEAM-____-OTLN
4 x Rive | GL28h | 0.07 | 0.22 | 3.58 | 3.388 | 2.0764 | 2.1072 | 0.0551 | 0.0551 | 0.2487 | 0.2487 | façade | Façade | S-BEAM-____-OTLN
2 x Solive | GL28h | 0.07 | 0.22 | 0.7414 | 3.388 | 0.43 | 0.4608 | 0.0114 | 0.0114 | 0.0515 | 0.0515 | plancher R+1 | Plancher Exterieur | S-BEAM-____-OTLN
Buton | GL28h | 0.26 | 0.26 | 7.7232 | 17.576 | 8.0321 | 8.1673 | 0.5221 | 0.5221 | 2.3552 | 2.3552 | structure poteau / poutre | Structure primaire | S-BEAM-____-OTLN
Solive | GL28h | 0.07 | 0.22 | 3.6999 | 3.388 | 2.1381 | 2.1689 | 0.057 | 0.0567 | 0.257 | 0.2559 | plancher R+1 | Plancher Exterieur | S-BEAM-____-OTLN
6 x Arbalétrier | GL28h | 0.07 | 0.22 | 1.2236 | 3.388 | 0.6931 | 0.7239 | 0.0188 | 0.0184 | 0.085 | 0.083 | charpente | Surtoiture | S-BEAM-____-OTLN
3 x Sommier | GL28h | 0.14 | 0.36 | 3.58 | 18.144 | 3.58 | 3.6808 | 0.1804 | 0.1804 | 0.8139 | 0.8139 | structure poteau / poutre | Structure primaire | S-BEAM-____-OTLN
Solive | GL28h | 0.07 | 0.22 | 4.0499 | 3.388 | 2.3447 | 2.3755 | 0.0624 | 0.0622 | 0.2813 | 0.2808 | plancher R+1 | Plancher Exterieur | S-BEAM-____-OTLN
Sommier | GL28h | 0.14 | 0.36 | 3.5801 | 18.144 | 3.5801 | 3.6809 | 0.1804 | 0.1804 | 0.814 | 0.814 | structure poteau / poutre | Structure primaire | S-BEAM-____-OTLN
2 x Sommier | GL28h | 0.14 | 0.32 | 3.86 | 14.336 | 3.5512 | 3.6408 | 0.1729 | 0.1729 | 0.7801 | 0.7801 | structure poteau / poutre | Plancher Exterieur
Buton | GL28h | 0.26 | 0.32 | 1.62 | 26.624 | 1.8792 | 2.0456 | 0.1348 | 0.1348 | 0.608 | 0.608 | structure poteau / poutre | Structure primaire | S-BEAM-____-OTLN
Solive | GL28h | 0.07 | 0.22 | 0.7412 | 3.388 | 0.4299 | 0.4607 | 0.0114 | 0.0114 | 0.0515 | 0.0515 | plancher R+1 | Plancher Exterieur | S-BEAM-____-OTLN
6 x Solive | GL28h | 0.07 | 0.22 | 1.0839 | 3.388 | 0.6287 | 0.6595 | 0.0167 | 0.0167 | 0.0753 | 0.0753 | plancher R+2 | Plancher Exterieur | S-BEAM-____-OTLN
Solive | GL28h | 0.07 | 0.22 | 0.7413 | 3.388 | 0.4299 | 0.4607 | 0.0114 | 0.0114 | 0.0515 | 0.0515 | plancher R+1 | Plancher Exterieur | S-BEAM-____-OTLN
Solive | GL28h | 0.07 | 0.22 | 1.53 | 3.388 | 0.8874 | 0.9182 | 0.0236 | 0.0236 | 0.1063 | 0.1063 | plancher R+2 | Plancher Exterieur | S-BEAM-____-OTLN
Buton | GL28h | 0.26 | 0.32 | 3.29 | 26.624 | 3.8164 | 3.9828 | 0.2737 | 0.2737 | 1.2348 | 1.2348 | structure poteau / poutre | Structure primaire | S-BEAM-____-OTLN
Solive | GL28h | 0.07 | 0.22 | 12.1432 | 3.388 | 7.043 | 7.0738 | 0.187 | 0.187 | 0.8436 | 0.8436 | plancher R+2 | Plancher Exterieur | S-BEAM-____-OTLN
Solive | GL28h | 0.07 | 0.22 | 11.0432 | 3.388 | 6.405 | 6.4358 | 0.1701 | 0.1701 | 0.7672 | 0.7672 | plancher R+1 | Plancher Exterieur | S-BEAM-____-OTLN
Solive | GL28h | 0.07 | 0.22 | 4.1227 | 3.388 | 2.3869 | 2.4177 | 0.0635 | 0.0634 | 0.2864 | 0.2858 | plancher R+1 | Plancher Exterieur | S-BEAM-____-OTLN
2 x garde corp | Moabi | 0.04 | 0.14 | 2.6564 | 0.784 | 0.9563 | 0.9675 | 0.0149 | 0.0149 | 9.6693 | 9.6693 | garde corp | Garde-corps | S-BEAM-____-OTLN
garde corp | Moabi | 0.04 | 0.14 | 10.7189 | 0.784 | 3.8588 | 3.87 | 0.06 | 0.06 | 39.0167 | 39.0167 | garde corp | Garde-corps | S-BEAM-____-OTLN
garde corp | Moabi | 0.04 | 0.14 | 2.6608 | 0.784 | 0.9579 | 0.9691 | 0.0149 | 0.0149 | 9.6853 | 9.6853 | garde corp | Garde-corps | S-BEAM-____-OTLN
garde corp | Moabi | 0.04 | 0.14 | 2.5973 | 0.784 | 0.935 | 0.9462 | 0.0145 | 0.0145 | 9.4543 | 9.4543 | garde corp | Garde-corps | S-BEAM-____-OTLN
garde corp | Moabi | 0.04 | 0.14 | 2.6313 | 0.784 | 0.9473 | 0.9585 | 0.0147 | 0.0147 | 9.5779 | 9.5779 | garde corp | Garde-corps | S-BEAM-____-OTLN

# IfcBuildingElementProxy (395)
In: Storey 1
Name | Material | Width (m) | Height (m) | Length (m) | CrossSectionArea (m2) | OuterfaceArea (m2) | TotalSurfaceArea (m2) | GrossVolume (m3) | NetVolume (m3) | GrossWeight | NetWeight | Group | SubGroup
 | C24 | 0 | 0 | 1.6078 | 0 | 0 | 0 | 0 | 0 | 0 | 0
20 x CVLP | Acier | 0.02 | 0.02 | 5.0558 | 0.0063 | 0.3177 | 0.3183 | 0.0016 | 0.0016 | 0.1222 | 0.1223 | charpente | Contreventement
20 x CVLP | Acier | 0.02 | 0.02 | 5.4036 | 0.0063 | 0.3395 | 0.3401 | 0.0017 | 0.0017 | 0.1306 | 0.1307 | charpente | Contreventement
20 x CVLP | Acier | 0.02 | 0.02 | 5.2663 | 0.0063 | 0.3309 | 0.3315 | 0.0017 | 0.0017 | 0.1273 | 0.1274 | charpente | Contreventement
34 x marche | Moabi | 0.04 | 0.28 | 1.3 | 3.136 | 0.832 | 0.8544 | 0.0146 | 0.0146 | 9.464 | 9.464 | escalier | Escalier | Pset cadwork 3d - Utilisateur 1: S-STRS-____-OTLN
48 x Poteau | Acier | 0.102 | 0.38 | 11.4207 | 3.0542 | 12.6898 | 12.7059 | 0.0918 | 0.0916 | 7.0687 | 7.0479
57 x lisse | GL28h | 0.07 | 0.22 | 0.7 | 3.388 | 0.406 | 0.4368 | 0.0108 | 0.0108 | 0.0486 | 0.0486 | façade | Façade
22 x CVLP | GL28h | 0.09 | 0.09 | 4.1962 | 0.729 | 1.5106 | 1.5268 | 0.034 | 0.034 | 0.1533 | 0.1533 | charpente | Contreventement
48 x marche | Moabi | 0.04 | 0.28 | 1.3 | 3.136 | 0.832 | 0.8544 | 0.0146 | 0.0146 | 9.464 | 9.464 | escalier | Escalier | Pset cadwork 3d - Utilisateur 1: S-STRS-____-OTLN; Prod_Nb: 7
2 x limon | GL28h | 0.07 | 0.4 | 4.3165 | 11.2 | 3.9211 | 3.9771 | 0.1209 | 0.1168 | 0.5452 | 0.527 | escalier | Escalier | Pset cadwork 3d - Utilisateur 1: S-STRS-____-OTLN; Prod_Nb: 6
8 x CVT | Acier | 0.02 | 0.02 | 5.0648 | 0.0063 | 0.3182 | 0.3189 | 0.0016 | 0.0016 | 0.1224 | 0.1225 | charpente | Contreventement
22 x CVLP | GL28h | 0.09 | 0.09 | 4.0711 | 0.729 | 1.4656 | 1.4818 | 0.033 | 0.033 | 0.1488 | 0.1488 | charpente | Contreventement
2 x Poteau | Acier | 0.102 | 0.38 | 8.8139 | 3.0542 | 9.7969 | 9.813 | 0.0709 | 0.0707 | 5.4552 | 5.4412
2 x Couverture | tôle | 0.1218 | 0.017 | 8.15 | 0.0352 | 2.198 | 2.2021 | 0.0169 | 0.0162 | 0 | 0 | couverture | Couverture - Etanchéité | Pset cadwork 3d - Utilisateur 1: A-ROOF-____-OTLN
2 x Couverture | tôle | 0.1218 | 0.017 | 20.42 | 0.0352 | 5.5073 | 5.5115 | 0.0423 | 0.0407 | 0 | 0 | couverture | Couverture - Etanchéité | Pset cadwork 3d - Utilisateur 1: A-ROOF-____-OTLN
2 x Couverture | tôle | 0.1218 | 0.017 | 6.0444 | 0.0352 | 1.6301 | 1.6342 | 0.0125 | 0.012 | 0 | 0 | couverture | Couverture - Etanchéité | Pset cadwork 3d - Utilisateur 1: A-ROOF-____-OTLN
2 x Couverture | tôle | 1.3 | 0.017 | 20.42 | 0.3757 | 53.7054 | 53.7496 | 0.4513 | 0.4505 | 0 | 0 | couverture | Couverture - Etanchéité | Pset cadwork 3d - Utilisateur 1: A-ROOF-____-OTLN
2 x Couverture | tôle | 7.8577 | 0.017 | 34.3144 | 2.2709 | 501.128 | 501.395 | 4.5838 | 4.2493 | 0 | 0 | couverture | Couverture - Etanchéité | Pset cadwork 3d - Utilisateur 1: A-ROOF-____-OTLN
4 x lisse | GL28h | 0.07 | 0.22 | 2.3516 | 3.388 | 1.3639 | 1.3947 | 0.0362 | 0.0362 | 0.1634 | 0.1634 | façade | Façade
2 x limon | GL28h | 0.07 | 0.4 | 4.3165 | 11.2 | 3.9211 | 3.9771 | 0.1209 | 0.1168 | 0.5452 | 0.527 | escalier | Escalier | Pset cadwork 3d - Utilisateur 1: S-STRS-____-OTLN
lisse | GL28h | 0.07 | 0.22 | 3.58 | 3.388 | 2.0764 | 2.1072 | 0.0551 | 0.0551 | 0.2487 | 0.2487 | façade | Façade
2 x lisse | GL28h | 0.07 | 0.22 | 2.74 | 3.388 | 1.5892 | 1.62 | 0.0422 | 0.0422 | 0.1903 | 0.1903 | façade | Façade
6 x marche | Moabi | 1.3 | 0.28 | 0.04 | 101.92 | 0.1264 | 0.8544 | 0.0146 | 0.0146 | 9.464 | 9.464 | escalier | Escalier | Pset cadwork 3d - Utilisateur 1: S-STRS-____-OTLN; Prod_Nb: 7
2 x limon | GL28h | 0.07 | 0.4 | 1.1123 | 11.2 | 0.945 | 1.001 | 0.0311 | 0.0281 | 0.1405 | 0.1267 | escalier | Escalier | Pset cadwork 3d - Utilisateur 1: S-STRS-____-OTLN
4 x limon | GL28h | 0.07 | 0.4 | 3.568 | 11.2 | 3.2175 | 3.2735 | 0.0999 | 0.0959 | 0.4507 | 0.4325 | escalier | Escalier | Pset cadwork 3d - Utilisateur 1: S-STRS-____-OTLN; Prod_Nb: 3
4 x limon | GL28h | 0.07 | 0.4 | 2.3171 | 11.2 | 2.0776 | 2.1336 | 0.0649 | 0.0618 | 0.2927 | 0.2789 | escalier | Escalier | Pset cadwork 3d - Utilisateur 1: S-STRS-____-OTLN; Prod_Nb: 2
2 x marche | Moabi | 2.4032 | 0.04 | 1.3 | 3.8451 | 6.3522 | 6.5445 | 0.125 | 0.125 | 81.2269 | 81.2269 | escalier | Escalier | Pset cadwork 3d - Utilisateur 1: S-STRS-____-OTLN; Prod_Nb: 9
3 x lisse | GL28h | 0.034 | 0.22 | 0.1 | 1.6456 | 0.0508 | 0.0658 | 0.0007 | 0.0007 | 0.0034 | 0.0034 | façade | Façade
32 x CVT | GL28h | 0.045 | 0.12 | 5.0648 | 0.648 | 1.6424 | 1.6532 | 0.0273 | 0.0268 | 0.1234 | 0.121 | charpente | Contreventement
2 x limon | GL28h | 0.07 | 0.4 | 3.3412 | 11.2 | 3.0012 | 3.0572 | 0.0936 | 0.0894 | 0.422 | 0.4034 | escalier | Escalier | Pset cadwork 3d - Utilisateur 1: S-STRS-____-OTLN; Prod_Nb: 4
2 x limon | GL28h | 0.07 | 0.4 | 1.1123 | 11.2 | 0.945 | 1.001 | 0.0311 | 0.0281 | 0.1405 | 0.1267 | escalier | Escalier | Pset cadwork 3d - Utilisateur 1: S-STRS-____-OTLN; Prod_Nb: 1
2 x limon | GL28h | 0.07 | 0.4 | 3.9912 | 11.2 | 3.6122 | 3.6682 | 0.1118 | 0.1076 | 0.5041 | 0.4855 | escalier | Escalier | Pset cadwork 3d - Utilisateur 1: S-STRS-____-OTLN
2 x limon | GL28h | 0.07 | 0.4 | 3.3412 | 11.2 | 3.0012 | 3.0572 | 0.0936 | 0.0894 | 0.422 | 0.4034 | escalier | Escalier | Pset cadwork 3d - Utilisateur 1: S-STRS-____-OTLN
lisse | GL28h | 0.07 | 0.22 | 7.7232 | 3.388 | 4.4794 | 4.5102 | 0.1189 | 0.1189 | 0.5365 | 0.5365 | façade | Façade
marche | Moabi | 1.2832 | 0.04 | 1.3 | 2.0531 | 3.4402 | 3.5429 | 0.0667 | 0.0667 | 43.3709 | 43.3709 | escalier | Escalier | Pset cadwork 3d - Utilisateur 1: S-STRS-____-OTLN
2 x limon | GL28h | 0.07 | 0.4 | 3.9912 | 11.2 | 3.6122 | 3.6682 | 0.1118 | 0.1076 | 0.5041 | 0.4855 | escalier | Escalier | Pset cadwork 3d - Utilisateur 1: S-STRS-____-OTLN; Prod_Nb: 5
marche | Moabi | 1.2832 | 0.04 | 1.3 | 2.0531 | 3.4402 | 3.5429 | 0.0667 | 0.0667 | 43.3709 | 43.3709 | escalier | Escalier | Pset cadwork 3d - Utilisateur 1: S-STRS-____-OTLN; Prod_Nb: 8
2 x lisse | GL28h | 0.07 | 0.22 | 0.81 | 3.388 | 0.4698 | 0.5006 | 0.0125 | 0.0125 | 0.0563 | 0.0563 | façade | Façade
2 x lisse | GL28h | 0.07 | 0.22 | 1.4132 | 3.388 | 0.8196 | 0.8504 | 0.0218 | 0.0218 | 0.0982 | 0.0982 | façade | Façade
lisse | GL28h | 0.07 | 0.22 | 1 | 3.388 | 0.58 | 0.6108 | 0.0154 | 0.0154 | 0.0695 | 0.0695 | façade | Façade
lisse | GL28h | 0.07 | 0.22 | 3.29 | 3.388 | 1.9082 | 1.939 | 0.0507 | 0.0507 | 0.2286 | 0.2286 | façade | Façade

# IfcColumn (248)
In: Storey 1
Material: GL28h
Name | Width (m) | Height (m) | Length (m) | CrossSectionArea (m2) | OuterfaceArea (m2) | TotalSurfaceArea (m2) | GrossVolume (m3) | NetVolume (m3) | GrossWeight | NetWeight | Group | SubGroup | Utilisateur 1
23 x poteau encadrement menuiserie | 0.12 | 0.26 | 3.055 | 8.112 | 2.3218 | 2.3842 | 0.0953 | 0.0953 | 0.43 | 0.43 | structure poteau / poutre | Façade | S-COLS-____-OTLN
40 x poteau encadrement menuiserie | 0.12 | 0.26 | 3.655 | 8.112 | 2.7778 | 2.8402 | 0.114 | 0.114 | 0.5144 | 0.5144 | structure poteau / poutre | Façade | S-COLS-____-OTLN
24 x Poteau | 0.16 | 0.46 | 10.8 | 33.856 | 13.392 | 13.5392 | 0.7949 | 0.7949 | 3.5858 | 3.5858 | structure poteau / poutre | Structure primaire | S-COLS-____-OTLN
23 x Fourrure | 0.1 | 0.26 | 3.629 | 6.76 | 2.6129 | 2.6649 | 0.0944 | 0.0944 | 0.4256 | 0.4256 | structure poteau / poutre | Structure primaire | S-COLS-____-OTLN
12 x poinçon | 0.14 | 0.32 | 1.9 | 14.336 | 1.6997 | 1.7893 | 0.0851 | 0.0832 | 0.384 | 0.3753 | charpente | Surtoiture | A-COLS-____-OTLN
12 x Fourrure | 0.1 | 0.26 | 3.571 | 6.76 | 2.5711 | 2.6231 | 0.0928 | 0.0928 | 0.4188 | 0.4188 | structure poteau / poutre | Structure primaire | S-COLS-____-OTLN
23 x Fourrure | 0.1 | 0.26 | 2.96 | 6.76 | 2.1312 | 2.1832 | 0.077 | 0.077 | 0.3472 | 0.3472 | structure poteau / poutre | Structure primaire | S-COLS-____-OTLN
4 x Poteau | 0.16 | 0.46 | 7.49 | 33.856 | 9.2876 | 9.4348 | 0.5513 | 0.5513 | 2.4868 | 2.4868 | structure poteau / poutre | Structure primaire | S-COLS-____-OTLN
8 x poteau | 0.14 | 0.42 | 7.49 | 24.696 | 8.3888 | 8.5064 | 0.4404 | 0.4404 | 1.9867 | 1.9867 | structure poteau / poutre | Structure primaire | S-COLS-____-OTLN
18 x poteau encadrement menuiserie | 0.12 | 0.26 | 3.3 | 8.112 | 2.508 | 2.5704 | 0.103 | 0.103 | 0.4645 | 0.4645 | structure poteau / poutre | Façade | S-COLS-____-OTLN
21 x poteau encadrement menuiserie | 0.12 | 0.26 | 3.285 | 8.112 | 2.4966 | 2.559 | 0.1025 | 0.1025 | 0.4623 | 0.4623 | structure poteau / poutre | Façade | S-COLS-____-OTLN
4 x poteau | 0.14 | 0.42 | 10.8 | 24.696 | 12.096 | 12.2136 | 0.635 | 0.635 | 2.8647 | 2.8647 | structure poteau / poutre | Structure primaire | S-COLS-____-OTLN
4 x poteau | 0.14 | 0.42 | 8.73 | 24.696 | 9.7776 | 9.8952 | 0.5133 | 0.5133 | 2.3156 | 2.3156 | structure poteau / poutre | Structure primaire | S-COLS-____-OTLN
12 x Poteau | 0.16 | 0.46 | 7.509 | 33.856 | 9.3112 | 9.4584 | 0.5527 | 0.5527 | 2.4931 | 2.4931 | structure poteau / poutre | Structure primaire | S-COLS-____-OTLN
10 x Poteau | 0.16 | 0.46 | 8.73 | 33.856 | 10.8252 | 10.9724 | 0.6425 | 0.6425 | 2.8985 | 2.8985 | structure poteau / poutre | Structure primaire | S-COLS-____-OTLN
poteau encadrement menuiserie | 0.12 | 0.26 | 3.595 | 8.112 | 2.7322 | 2.7946 | 0.1122 | 0.1122 | 0.506 | 0.506 | structure poteau / poutre | Façade | S-COLS-____-OTLN
5 x Fourrure | 0.1 | 0.26 | 1.501 | 6.76 | 1.0807 | 1.1327 | 0.039 | 0.039 | 0.176 | 0.176 | structure poteau / poutre | Structure primaire | S-COLS-____-OTLN
poteau encadrement menuiserie | 0.12 | 0.26 | 1.43 | 8.112 | 1.0868 | 1.1492 | 0.0446 | 0.0446 | 0.2013 | 0.2013 | structure poteau / poutre | Façade | S-COLS-____-OTLN
poteau encadrement menuiserie | 0.12 | 0.26 | 3.24 | 8.112 | 2.4624 | 2.5248 | 0.1011 | 0.1011 | 0.456 | 0.456 | structure poteau / poutre | Façade | S-COLS-____-OTLN
2 x poteau encadrement menuiserie | 0.12 | 0.26 | 1 | 8.112 | 0.76 | 0.8224 | 0.0312 | 0.0312 | 0.1407 | 0.1407 | structure poteau / poutre | Façade | S-COLS-____-OTLN

# IfcFlowSegment (2)
In: Storey 1
Material: Zinc
BaseQuantities - Width: 0.1524 m; Height: 0.1524 m; Length: 34.0972 m; CrossSectionArea: 3.5396 m2; OuterfaceArea: 29.4206 m2; TotalSurfaceArea: 29.467 m2; GrossVolume: 0.7919 m3; NetVolume: 0.352 m3; GrossWeight: 55.5285; NetWeight: 24.6793
Pset cadwork 3d - Group: couverture; SubGroup: Couverture - Etanchéité; Utilisateur 1: A-ROOF-____-OTLN

# IfcRoof (4)
In: Storey 1
BaseQuantities - Height: 0.017 m; GrossWeight: 0; NetWeight: 0
Pset cadwork 3d - Group: couverture; SubGroup: Couverture - Etanchéité; Utilisateur 1: A-ROOF-____-OTLN
Name | Width (m) | Length (m) | CrossSectionArea (m2) | OuterfaceArea (m2) | TotalSurfaceArea (m2) | GrossVolume (m3) | NetVolume (m3)
2 x Roof - Couverture | 1.3 | 20.42 | 0.3757 | 53.7054 | 53.7496 | 0.4513 | 0.4505
2 x Roof - Couverture | 7.8577 | 34.3144 | 2.2709 | 501.128 | 501.395 | 4.5838 | 4.2493

# IfcSlab (43)
In: Storey 1
Pset cadwork 3d - Utilisateur 1: A-FLOR-____-OTLN
Name | Material | Width (m) | Height (m) | Length (m) | CrossSectionArea (m2) | OuterfaceArea (m2) | TotalSurfaceArea (m2) | GrossVolume (m3) | NetVolume (m3) | GrossWeight | NetWeight | Group | SubGroup
platelage | Moabi | 3.5 | 0.021 | 9.2827 | 1.5435 | 51.8508 | 51.9978 | 0.6823 | 0.5408 | 443.482 | 351.517 | plancher extérieur | Platelage
platelage | Moabi | 4.5 | 0.021 | 19.308 | 1.9845 | 118.081 | 118.27 | 1.8246 | 1.2321 | 1185.99 | 800.861 | plancher extérieur | Platelage
platelage | Ipé | 12.2288 | 0.021 | 49.3189 | 5.3929 | 761.151 | 761.664 | 12.6653 | 7.9472 | 130.414 | 81.8324 | plancher R+2 | Platelage
2 x isolant sur CLT | Polystyrène expansé | 4.0058 | 0.08 | 16.18 | 25.637 | 132.139 | 132.78 | 5.1851 | 5.182 | 1.017 | 1.0164 | plancher R+2 | Couverture - Etanchéité
2 x isolant sur CLT | Polystyrène expansé | 3.8816 | 0.08 | 4.0258 | 24.8424 | 31.8787 | 32.4997 | 1.2501 | 1.2494 | 0.2452 | 0.245 | plancher R+2 | Couverture - Etanchéité
6 x CLT | Cryptoméria | 3.58 | 0.1 | 3.9835 | 35.8 | 29.3077 | 30.0237 | 1.4261 | 1.4256 | 591.83 | 591.607 | Charpente | Support Etanchéité
2 x CLT | Cryptoméria | 3.869 | 0.14 | 7.9632 | 75.8324 | 63.8486 | 64.932 | 4.3133 | 4.3133 | 1790.03 | 1790.03 | Charpente | Plancher intérieur
2 x CLT | Cryptoméria | 3.86 | 0.1 | 3.9835 | 38.6 | 31.5376 | 32.3096 | 1.5376 | 1.5371 | 638.119 | 637.878 | Charpente | Support Etanchéité
2 x CLT | Cryptoméria | 3.88 | 0.15 | 3.9879 | 87.3 | 32.1065 | 33.2705 | 2.3209 | 2.3183 | 963.191 | 962.104 | Charpente | Support Etanchéité
2 x CLT | Cryptoméria | 3.72 | 0.1 | 3.9835 | 37.2 | 30.4227 | 31.1667 | 1.4819 | 1.4813 | 614.975 | 614.743 | Charpente | Support Etanchéité
CLT | Cryptoméria | 3.88 | 0.15 | 3.9879 | 87.3 | 32.1064 | 33.2704 | 2.3209 | 2.3183 | 963.187 | 962.1 | Charpente | Plancher intérieur
2 x CLT | Cryptoméria | 3.86 | 0.14 | 7.9632 | 75.656 | 63.7053 | 64.7861 | 4.3033 | 4.3033 | 1785.87 | 1785.87 | Charpente | Plancher intérieur
2 x CLT | Cryptoméria | 3.58 | 0.14 | 7.9632 | 70.168 | 58.8859 | 59.8883 | 3.9911 | 3.9561 | 1656.32 | 1641.8 | Charpente | Plancher intérieur
platelage | Ipé | 11.5288 | 0.021 | 53.092 | 5.0842 | 531.207 | 531.692 | 12.8538 | 5.5306 | 132.355 | 56.9487 | plancher R+1 | Platelage
CLT | Cryptoméria | 3.58 | 0.15 | 3.9879 | 80.55 | 29.7166 | 30.7906 | 2.1415 | 2.1391 | 888.721 | 887.719 | Charpente | Plancher intérieur
CLT | Cryptoméria | 3.58 | 0.15 | 3.9879 | 80.55 | 29.7163 | 30.7903 | 2.1415 | 2.1391 | 888.713 | 887.711 | Charpente | Plancher intérieur
CLT | Cryptoméria | 3.88 | 0.15 | 3.9879 | 87.3 | 32.1067 | 33.2707 | 2.321 | 2.3183 | 963.195 | 962.108 | Charpente | Plancher intérieur
8 x CLT | Cryptoméria | 3.58 | 0.14 | 7.9632 | 70.168 | 59.2459 | 60.2483 | 3.9911 | 3.9911 | 1656.32 | 1656.32 | Charpente | Plancher intérieur
CLT | Cryptoméria | 3.58 | 0.15 | 3.9879 | 80.55 | 29.7166 | 30.7906 | 2.1415 | 2.1391 | 888.721 | 887.719 | Charpente | Support Etanchéité
CLT | Cryptoméria | 3.869 | 0.15 | 3.9879 | 87.0525 | 32.0187 | 33.1794 | 2.3144 | 2.3117 | 960.456 | 959.372 | Charpente | Support Etanchéité
CLT | Cryptoméria | 3.58 | 0.15 | 3.9879 | 80.55 | 29.7163 | 30.7903 | 2.1415 | 2.1391 | 888.713 | 887.711 | Charpente | Support Etanchéité
CLT | Cryptoméria | 3.86 | 0.14 | 7.9632 | 75.656 | 54.1925 | 55.2733 | 4.3033 | 3.6374 | 1785.87 | 1509.52 | Charpente | Plancher intérieur
CLT | Cryptoméria | 3.869 | 0.15 | 3.9879 | 87.0525 | 32.019 | 33.1797 | 2.3144 | 2.3118 | 960.465 | 959.381 | Charpente | Support Etanchéité

# IfcWall (2)
In: Storey 1
BaseQuantities - Width: 3.285 m; Length: 7.9632 m
Pset cadwork 3d - Group: façade; SubGroup: Façade OB
Name | Material | Height (m) | CrossSectionArea (m2) | OuterfaceArea (m2) | TotalSurfaceArea (m2) | GrossVolume (m3) | NetVolume (m3) | GrossWeight | NetWeight
paroi | Paroi | 0.12 | 47.304 | 36.2387 | 37.0271 | 3.1391 | 1.9295 | 0 | 0
paroi | Bardage | 0.02 | 1.314 | 32.8381 | 32.9695 | 0.5232 | 0.3216 | 2.5653 | 1.5768
